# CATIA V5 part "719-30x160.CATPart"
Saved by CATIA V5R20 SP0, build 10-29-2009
Part number: 719-30x160
Definition: NONE
Nomenclature: 719-30x160
Source: Unknown
Description: 719-30x160
Bounding box of the stored display mesh (mm): x 0 to 197, y -20 to 20, z -20 to 20
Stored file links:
  C:\Users\Utente\Desktop\IO LAVORO\3D X SITO CF\X SITO\719\719-30x160.CATPart

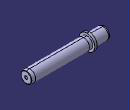
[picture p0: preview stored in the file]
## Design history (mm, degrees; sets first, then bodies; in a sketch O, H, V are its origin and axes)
Body1 "719-30x160" (main body)
  Solid1: solid without history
